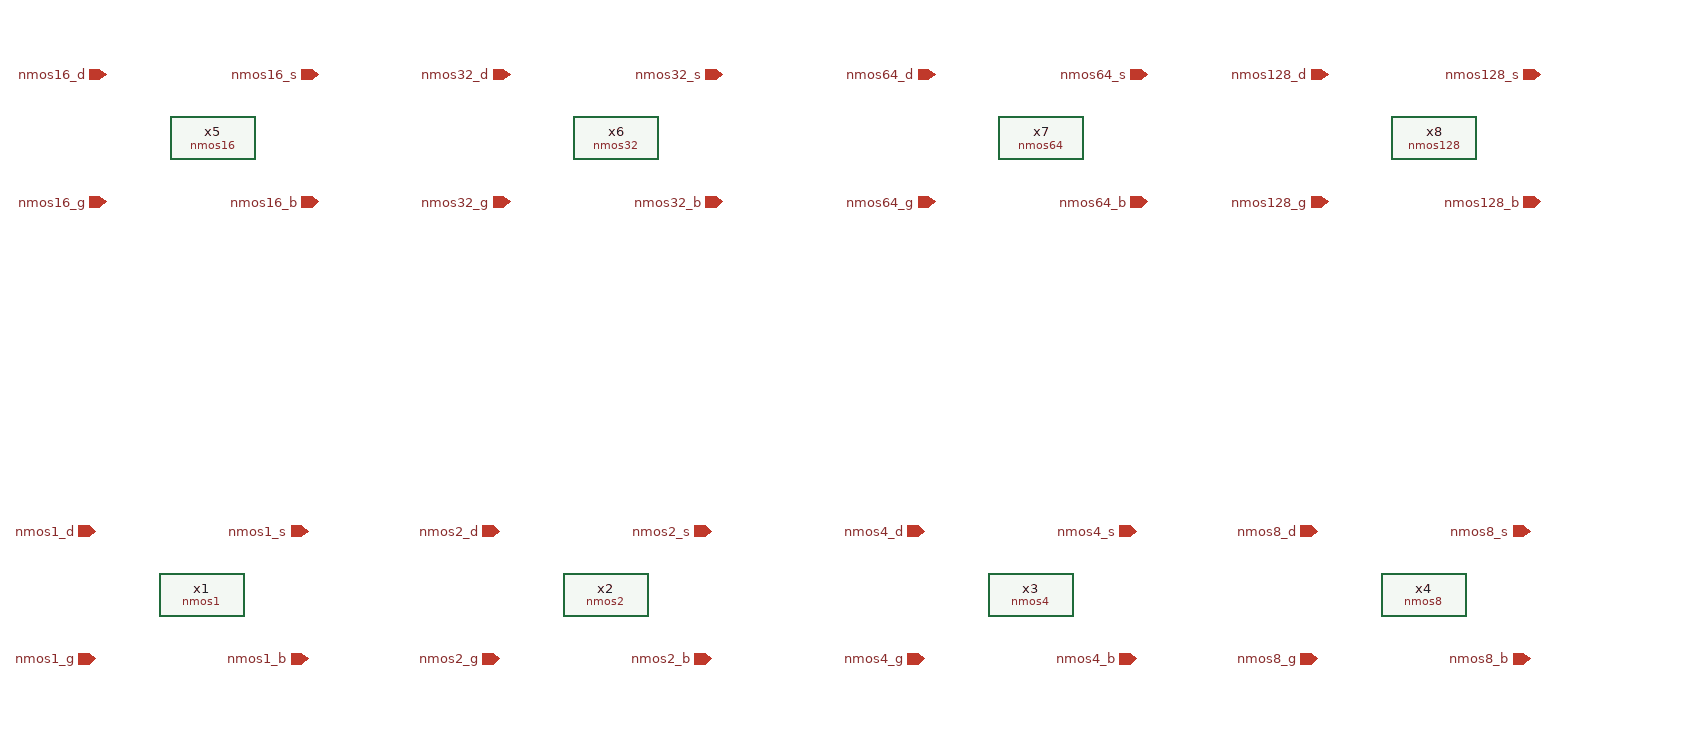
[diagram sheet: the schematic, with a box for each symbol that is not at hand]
v {xschem version=3.4.5 file_version=1.2
}
G {}
K {}
V {}
S {}
E {}
C {nmos1.sym} -580 650 0 0 {name=x1}
C {devices/iopin.sym} -680 590 3 0 {name=p1 lab=nmos1_d}
C {devices/iopin.sym} -480 590 3 0 {name=p2 lab=nmos1_s}
C {devices/iopin.sym} -480 710 1 0 {name=p3 lab=nmos1_b}
C {devices/iopin.sym} -680 710 1 0 {name=p4 lab=nmos1_g}
C {devices/iopin.sym} -300 590 3 0 {name=p5 lab=nmos2_d}
C {devices/iopin.sym} -100 590 3 0 {name=p6 lab=nmos2_s}
C {devices/iopin.sym} -100 710 1 0 {name=p7 lab=nmos2_b}
C {devices/iopin.sym} -300 710 1 0 {name=p8 lab=nmos2_g}
C {nmos2.sym} -200 650 0 0 {name=x2}
C {devices/iopin.sym} 100 590 3 0 {name=p9 lab=nmos4_d}
C {devices/iopin.sym} 300 590 3 0 {name=p10 lab=nmos4_s}
C {devices/iopin.sym} 300 710 1 0 {name=p11 lab=nmos4_b}
C {devices/iopin.sym} 100 710 1 0 {name=p12 lab=nmos4_g}
C {nmos4.sym} 200 650 0 0 {name=x3}
C {devices/iopin.sym} 470 590 3 0 {name=p13 lab=nmos8_d}
C {devices/iopin.sym} 670 590 3 0 {name=p14 lab=nmos8_s}
C {devices/iopin.sym} 670 710 1 0 {name=p15 lab=nmos8_b}
C {devices/iopin.sym} 470 710 1 0 {name=p16 lab=nmos8_g}
C {nmos8.sym} 570 650 0 0 {name=x4}
C {devices/iopin.sym} -670 160 3 0 {name=p17 lab=nmos16_d}
C {devices/iopin.sym} -470 160 3 0 {name=p18 lab=nmos16_s}
C {devices/iopin.sym} -470 280 1 0 {name=p19 lab=nmos16_b}
C {devices/iopin.sym} -670 280 1 0 {name=p20 lab=nmos16_g}
C {devices/iopin.sym} -290 160 3 0 {name=p21 lab=nmos32_d}
C {devices/iopin.sym} -90 160 3 0 {name=p22 lab=nmos32_s}
C {devices/iopin.sym} -90 280 1 0 {name=p23 lab=nmos32_b}
C {devices/iopin.sym} -290 280 1 0 {name=p24 lab=nmos32_g}
C {devices/iopin.sym} 110 160 3 0 {name=p25 lab=nmos64_d}
C {devices/iopin.sym} 310 160 3 0 {name=p26 lab=nmos64_s}
C {devices/iopin.sym} 310 280 1 0 {name=p27 lab=nmos64_b}
C {devices/iopin.sym} 110 280 1 0 {name=p28 lab=nmos64_g}
C {devices/iopin.sym} 480 160 3 0 {name=p29 lab=nmos128_d}
C {devices/iopin.sym} 680 160 3 0 {name=p30 lab=nmos128_s}
C {devices/iopin.sym} 680 280 1 0 {name=p31 lab=nmos128_b}
C {devices/iopin.sym} 480 280 1 0 {name=p32 lab=nmos128_g}
C {nmos16.sym} -570 220 0 0 {name=x5}
C {nmos32.sym} -190 220 0 0 {name=x6}
C {nmos64.sym} 210 220 0 0 {name=x7}
C {nmos128.sym} 580 220 0 0 {name=x8}
